VERSION 5.7 ;
  NOWIREEXTENSIONATPIN ON ;
  DIVIDERCHAR "/" ;
  BUSBITCHARS "[]" ;
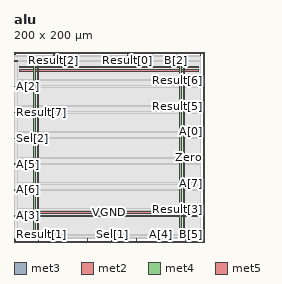
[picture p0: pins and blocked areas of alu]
MACRO alu
  CLASS BLOCK ;
  FOREIGN alu ;
  ORIGIN 0.000 0.000 ;
  SIZE 200.000 BY 200.000 ;
  PIN A[0]
    DIRECTION INPUT ;
    USE SIGNAL ;
    ANTENNAGATEAREA 0.213000 ;
    PORT
      LAYER met3 ;
        RECT 196.000 115.640 200.000 116.240 ;
    END
  END A[0]
  PIN A[1]
    DIRECTION INPUT ;
    USE SIGNAL ;
    ANTENNAGATEAREA 0.196500 ;
    PORT
      LAYER met2 ;
        RECT 51.610 0.000 51.890 4.000 ;
    END
  END A[1]
  PIN A[2]
    DIRECTION INPUT ;
    USE SIGNAL ;
    ANTENNAGATEAREA 0.213000 ;
    PORT
      LAYER met3 ;
        RECT 0.000 163.240 4.000 163.840 ;
    END
  END A[2]
  PIN A[3]
    DIRECTION INPUT ;
    USE SIGNAL ;
    ANTENNAGATEAREA 0.247500 ;
    PORT
      LAYER met3 ;
        RECT 0.000 27.240 4.000 27.840 ;
    END
  END A[3]
  PIN A[4]
    DIRECTION INPUT ;
    USE SIGNAL ;
    ANTENNAGATEAREA 0.196500 ;
    PORT
      LAYER met2 ;
        RECT 154.650 0.000 154.930 4.000 ;
    END
  END A[4]
  PIN A[5]
    DIRECTION INPUT ;
    USE SIGNAL ;
    ANTENNAGATEAREA 0.159000 ;
    PORT
      LAYER met3 ;
        RECT 0.000 81.640 4.000 82.240 ;
    END
  END A[5]
  PIN A[6]
    DIRECTION INPUT ;
    USE SIGNAL ;
    ANTENNAGATEAREA 0.159000 ;
    PORT
      LAYER met3 ;
        RECT 0.000 54.440 4.000 55.040 ;
    END
  END A[6]
  PIN A[7]
    DIRECTION INPUT ;
    USE SIGNAL ;
    ANTENNAGATEAREA 0.213000 ;
    PORT
      LAYER met3 ;
        RECT 196.000 61.240 200.000 61.840 ;
    END
  END A[7]
  PIN B[0]
    DIRECTION INPUT ;
    USE SIGNAL ;
    ANTENNAGATEAREA 0.126000 ;
    PORT
      LAYER met2 ;
        RECT 67.710 196.000 67.990 200.000 ;
    END
  END B[0]
  PIN B[1]
    DIRECTION INPUT ;
    USE SIGNAL ;
    ANTENNAGATEAREA 0.213000 ;
    PORT
      LAYER met2 ;
        RECT 0.090 0.000 0.370 4.000 ;
    END
  END B[1]
  PIN B[2]
    DIRECTION INPUT ;
    USE SIGNAL ;
    ANTENNAGATEAREA 0.213000 ;
    PORT
      LAYER met2 ;
        RECT 170.750 196.000 171.030 200.000 ;
    END
  END B[2]
  PIN B[3]
    DIRECTION INPUT ;
    USE SIGNAL ;
    ANTENNAGATEAREA 0.213000 ;
    PORT
      LAYER met2 ;
        RECT 196.510 196.000 196.790 200.000 ;
    END
  END B[3]
  PIN B[4]
    DIRECTION INPUT ;
    USE SIGNAL ;
    ANTENNAGATEAREA 0.213000 ;
    PORT
      LAYER met2 ;
        RECT 144.990 196.000 145.270 200.000 ;
    END
  END B[4]
  PIN B[5]
    DIRECTION INPUT ;
    USE SIGNAL ;
    ANTENNAGATEAREA 0.126000 ;
    PORT
      LAYER met3 ;
        RECT 196.000 6.840 200.000 7.440 ;
    END
  END B[5]
  PIN B[6]
    DIRECTION INPUT ;
    USE SIGNAL ;
    ANTENNAGATEAREA 0.126000 ;
    PORT
      LAYER met2 ;
        RECT 128.890 0.000 129.170 4.000 ;
    END
  END B[6]
  PIN B[7]
    DIRECTION INPUT ;
    USE SIGNAL ;
    ANTENNAGATEAREA 0.213000 ;
    PORT
      LAYER met2 ;
        RECT 16.190 196.000 16.470 200.000 ;
    END
  END B[7]
  PIN CarryOut
    DIRECTION OUTPUT TRISTATE ;
    USE SIGNAL ;
    ANTENNADIFFAREA 0.795200 ;
    PORT
      LAYER met2 ;
        RECT 180.410 0.000 180.690 4.000 ;
    END
  END CarryOut
  PIN Result[0]
    DIRECTION OUTPUT TRISTATE ;
    USE SIGNAL ;
    ANTENNADIFFAREA 0.795200 ;
    PORT
      LAYER met2 ;
        RECT 119.230 196.000 119.510 200.000 ;
    END
  END Result[0]
  PIN Result[1]
    DIRECTION OUTPUT TRISTATE ;
    USE SIGNAL ;
    ANTENNADIFFAREA 0.795200 ;
    PORT
      LAYER met2 ;
        RECT 25.850 0.000 26.130 4.000 ;
    END
  END Result[1]
  PIN Result[2]
    DIRECTION OUTPUT TRISTATE ;
    USE SIGNAL ;
    ANTENNADIFFAREA 0.795200 ;
    PORT
      LAYER met2 ;
        RECT 41.950 196.000 42.230 200.000 ;
    END
  END Result[2]
  PIN Result[3]
    DIRECTION OUTPUT TRISTATE ;
    USE SIGNAL ;
    ANTENNADIFFAREA 0.795200 ;
    PORT
      LAYER met3 ;
        RECT 196.000 34.040 200.000 34.640 ;
    END
  END Result[3]
  PIN Result[4]
    DIRECTION OUTPUT TRISTATE ;
    USE SIGNAL ;
    ANTENNADIFFAREA 0.795200 ;
    PORT
      LAYER met2 ;
        RECT 77.370 0.000 77.650 4.000 ;
    END
  END Result[4]
  PIN Result[5]
    DIRECTION OUTPUT TRISTATE ;
    USE SIGNAL ;
    ANTENNADIFFAREA 0.795200 ;
    PORT
      LAYER met3 ;
        RECT 196.000 142.840 200.000 143.440 ;
    END
  END Result[5]
  PIN Result[6]
    DIRECTION OUTPUT TRISTATE ;
    USE SIGNAL ;
    ANTENNADIFFAREA 0.795200 ;
    PORT
      LAYER met3 ;
        RECT 196.000 170.040 200.000 170.640 ;
    END
  END Result[6]
  PIN Result[7]
    DIRECTION OUTPUT TRISTATE ;
    USE SIGNAL ;
    ANTENNADIFFAREA 0.795200 ;
    PORT
      LAYER met3 ;
        RECT 0.000 136.040 4.000 136.640 ;
    END
  END Result[7]
  PIN Sel[0]
    DIRECTION INPUT ;
    USE SIGNAL ;
    ANTENNAGATEAREA 0.196500 ;
    PORT
      LAYER met2 ;
        RECT 93.470 196.000 93.750 200.000 ;
    END
  END Sel[0]
  PIN Sel[1]
    DIRECTION INPUT ;
    USE SIGNAL ;
    ANTENNAGATEAREA 0.213000 ;
    PORT
      LAYER met2 ;
        RECT 103.130 0.000 103.410 4.000 ;
    END
  END Sel[1]
  PIN Sel[2]
    DIRECTION INPUT ;
    USE SIGNAL ;
    ANTENNAGATEAREA 0.213000 ;
    PORT
      LAYER met3 ;
        RECT 0.000 108.840 4.000 109.440 ;
    END
  END Sel[2]
  PIN Sel[3]
    DIRECTION INPUT ;
    USE SIGNAL ;
    ANTENNAGATEAREA 0.159000 ;
    PORT
      LAYER met3 ;
        RECT 0.000 190.440 4.000 191.040 ;
    END
  END Sel[3]
  PIN VGND
    DIRECTION INOUT ;
    USE GROUND ;
    PORT
      LAYER met4 ;
        RECT 24.340 10.640 25.940 187.920 ;
    END
    PORT
      LAYER met4 ;
        RECT 177.940 10.640 179.540 187.920 ;
    END
    PORT
      LAYER met5 ;
        RECT 5.280 30.030 194.360 31.630 ;
    END
    PORT
      LAYER met5 ;
        RECT 5.280 183.210 194.360 184.810 ;
    END
  END VGND
  PIN VPWR
    DIRECTION INOUT ;
    USE POWER ;
    PORT
      LAYER met4 ;
        RECT 21.040 10.640 22.640 187.920 ;
    END
    PORT
      LAYER met4 ;
        RECT 174.640 10.640 176.240 187.920 ;
    END
    PORT
      LAYER met5 ;
        RECT 5.280 26.730 194.360 28.330 ;
    END
    PORT
      LAYER met5 ;
        RECT 5.280 179.910 194.360 181.510 ;
    END
  END VPWR
  PIN Zero
    DIRECTION OUTPUT TRISTATE ;
    USE SIGNAL ;
    ANTENNADIFFAREA 0.891000 ;
    PORT
      LAYER met3 ;
        RECT 196.000 88.440 200.000 89.040 ;
    END
  END Zero
  OBS
      LAYER li1 ;
        RECT 5.520 10.795 194.120 187.765 ;
      LAYER met1 ;
        RECT 0.070 10.640 196.810 187.920 ;
      LAYER met2 ;
        RECT 0.100 195.720 15.910 196.000 ;
        RECT 16.750 195.720 41.670 196.000 ;
        RECT 42.510 195.720 67.430 196.000 ;
        RECT 68.270 195.720 93.190 196.000 ;
        RECT 94.030 195.720 118.950 196.000 ;
        RECT 119.790 195.720 144.710 196.000 ;
        RECT 145.550 195.720 170.470 196.000 ;
        RECT 171.310 195.720 196.230 196.000 ;
        RECT 0.100 4.280 196.780 195.720 ;
        RECT 0.650 4.000 25.570 4.280 ;
        RECT 26.410 4.000 51.330 4.280 ;
        RECT 52.170 4.000 77.090 4.280 ;
        RECT 77.930 4.000 102.850 4.280 ;
        RECT 103.690 4.000 128.610 4.280 ;
        RECT 129.450 4.000 154.370 4.280 ;
        RECT 155.210 4.000 180.130 4.280 ;
        RECT 180.970 4.000 196.780 4.280 ;
      LAYER met3 ;
        RECT 4.400 190.040 196.000 190.890 ;
        RECT 4.000 171.040 196.000 190.040 ;
        RECT 4.000 169.640 195.600 171.040 ;
        RECT 4.000 164.240 196.000 169.640 ;
        RECT 4.400 162.840 196.000 164.240 ;
        RECT 4.000 143.840 196.000 162.840 ;
        RECT 4.000 142.440 195.600 143.840 ;
        RECT 4.000 137.040 196.000 142.440 ;
        RECT 4.400 135.640 196.000 137.040 ;
        RECT 4.000 116.640 196.000 135.640 ;
        RECT 4.000 115.240 195.600 116.640 ;
        RECT 4.000 109.840 196.000 115.240 ;
        RECT 4.400 108.440 196.000 109.840 ;
        RECT 4.000 89.440 196.000 108.440 ;
        RECT 4.000 88.040 195.600 89.440 ;
        RECT 4.000 82.640 196.000 88.040 ;
        RECT 4.400 81.240 196.000 82.640 ;
        RECT 4.000 62.240 196.000 81.240 ;
        RECT 4.000 60.840 195.600 62.240 ;
        RECT 4.000 55.440 196.000 60.840 ;
        RECT 4.400 54.040 196.000 55.440 ;
        RECT 4.000 35.040 196.000 54.040 ;
        RECT 4.000 33.640 195.600 35.040 ;
        RECT 4.000 28.240 196.000 33.640 ;
        RECT 4.400 26.840 196.000 28.240 ;
        RECT 4.000 7.840 196.000 26.840 ;
        RECT 4.000 6.975 195.600 7.840 ;
  END
END alu
END LIBRARY

